VERSION 5.7 ;
  NOWIREEXTENSIONATPIN ON ;
  DIVIDERCHAR "/" ;
  BUSBITCHARS "[]" ;
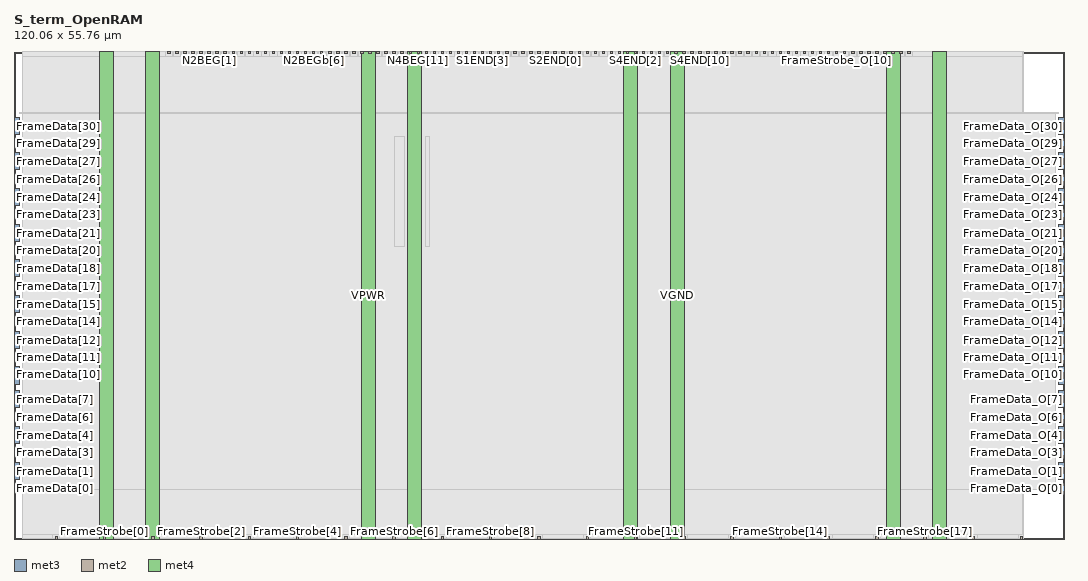
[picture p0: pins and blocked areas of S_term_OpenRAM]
MACRO S_term_OpenRAM
  CLASS BLOCK ;
  FOREIGN S_term_OpenRAM ;
  ORIGIN 0.000 0.000 ;
  SIZE 120.060 BY 55.760 ;
  PIN FrameData[0]
    DIRECTION INPUT ;
    USE SIGNAL ;
    ANTENNAGATEAREA 0.196500 ;
    PORT
      LAYER met3 ;
        RECT 0.000 5.480 0.600 6.080 ;
    END
  END FrameData[0]
  PIN FrameData[10]
    DIRECTION INPUT ;
    USE SIGNAL ;
    ANTENNAGATEAREA 0.631200 ;
    ANTENNADIFFAREA 0.434700 ;
    PORT
      LAYER met3 ;
        RECT 0.000 19.080 0.600 19.680 ;
    END
  END FrameData[10]
  PIN FrameData[11]
    DIRECTION INPUT ;
    USE SIGNAL ;
    ANTENNAGATEAREA 0.631200 ;
    ANTENNADIFFAREA 0.434700 ;
    PORT
      LAYER met3 ;
        RECT 0.000 20.440 0.600 21.040 ;
    END
  END FrameData[11]
  PIN FrameData[12]
    DIRECTION INPUT ;
    USE SIGNAL ;
    ANTENNAGATEAREA 0.631200 ;
    ANTENNADIFFAREA 0.434700 ;
    PORT
      LAYER met3 ;
        RECT 0.000 21.800 0.600 22.400 ;
    END
  END FrameData[12]
  PIN FrameData[13]
    DIRECTION INPUT ;
    USE SIGNAL ;
    ANTENNAGATEAREA 0.196500 ;
    PORT
      LAYER met3 ;
        RECT 0.000 23.160 0.600 23.760 ;
    END
  END FrameData[13]
  PIN FrameData[14]
    DIRECTION INPUT ;
    USE SIGNAL ;
    ANTENNAGATEAREA 0.196500 ;
    PORT
      LAYER met3 ;
        RECT 0.000 24.520 0.600 25.120 ;
    END
  END FrameData[14]
  PIN FrameData[15]
    DIRECTION INPUT ;
    USE SIGNAL ;
    ANTENNAGATEAREA 0.196500 ;
    PORT
      LAYER met3 ;
        RECT 0.000 25.880 0.600 26.480 ;
    END
  END FrameData[15]
  PIN FrameData[16]
    DIRECTION INPUT ;
    USE SIGNAL ;
    ANTENNAGATEAREA 0.196500 ;
    PORT
      LAYER met3 ;
        RECT 0.000 27.240 0.600 27.840 ;
    END
  END FrameData[16]
  PIN FrameData[17]
    DIRECTION INPUT ;
    USE SIGNAL ;
    ANTENNAGATEAREA 0.196500 ;
    PORT
      LAYER met3 ;
        RECT 0.000 28.600 0.600 29.200 ;
    END
  END FrameData[17]
  PIN FrameData[18]
    DIRECTION INPUT ;
    USE SIGNAL ;
    ANTENNAGATEAREA 0.196500 ;
    PORT
      LAYER met3 ;
        RECT 0.000 29.960 0.600 30.560 ;
    END
  END FrameData[18]
  PIN FrameData[19]
    DIRECTION INPUT ;
    USE SIGNAL ;
    ANTENNAGATEAREA 0.631200 ;
    ANTENNADIFFAREA 0.434700 ;
    PORT
      LAYER met3 ;
        RECT 0.000 31.320 0.600 31.920 ;
    END
  END FrameData[19]
  PIN FrameData[1]
    DIRECTION INPUT ;
    USE SIGNAL ;
    ANTENNAGATEAREA 0.196500 ;
    PORT
      LAYER met3 ;
        RECT 0.000 6.840 0.600 7.440 ;
    END
  END FrameData[1]
  PIN FrameData[20]
    DIRECTION INPUT ;
    USE SIGNAL ;
    ANTENNAGATEAREA 0.196500 ;
    PORT
      LAYER met3 ;
        RECT 0.000 32.680 0.600 33.280 ;
    END
  END FrameData[20]
  PIN FrameData[21]
    DIRECTION INPUT ;
    USE SIGNAL ;
    ANTENNAGATEAREA 0.196500 ;
    PORT
      LAYER met3 ;
        RECT 0.000 34.040 0.600 34.640 ;
    END
  END FrameData[21]
  PIN FrameData[22]
    DIRECTION INPUT ;
    USE SIGNAL ;
    ANTENNAGATEAREA 0.631200 ;
    ANTENNADIFFAREA 0.434700 ;
    PORT
      LAYER met3 ;
        RECT 0.000 35.400 0.600 36.000 ;
    END
  END FrameData[22]
  PIN FrameData[23]
    DIRECTION INPUT ;
    USE SIGNAL ;
    ANTENNAGATEAREA 0.196500 ;
    PORT
      LAYER met3 ;
        RECT 0.000 36.760 0.600 37.360 ;
    END
  END FrameData[23]
  PIN FrameData[24]
    DIRECTION INPUT ;
    USE SIGNAL ;
    ANTENNAGATEAREA 0.631200 ;
    ANTENNADIFFAREA 0.434700 ;
    PORT
      LAYER met3 ;
        RECT 0.000 38.120 0.600 38.720 ;
    END
  END FrameData[24]
  PIN FrameData[25]
    DIRECTION INPUT ;
    USE SIGNAL ;
    ANTENNAGATEAREA 0.631200 ;
    ANTENNADIFFAREA 0.434700 ;
    PORT
      LAYER met3 ;
        RECT 0.000 39.480 0.600 40.080 ;
    END
  END FrameData[25]
  PIN FrameData[26]
    DIRECTION INPUT ;
    USE SIGNAL ;
    ANTENNAGATEAREA 0.631200 ;
    ANTENNADIFFAREA 0.434700 ;
    PORT
      LAYER met3 ;
        RECT 0.000 40.840 0.600 41.440 ;
    END
  END FrameData[26]
  PIN FrameData[27]
    DIRECTION INPUT ;
    USE SIGNAL ;
    ANTENNAGATEAREA 0.631200 ;
    ANTENNADIFFAREA 0.434700 ;
    PORT
      LAYER met3 ;
        RECT 0.000 42.200 0.600 42.800 ;
    END
  END FrameData[27]
  PIN FrameData[28]
    DIRECTION INPUT ;
    USE SIGNAL ;
    ANTENNAGATEAREA 0.631200 ;
    ANTENNADIFFAREA 0.434700 ;
    PORT
      LAYER met3 ;
        RECT 0.000 43.560 0.600 44.160 ;
    END
  END FrameData[28]
  PIN FrameData[29]
    DIRECTION INPUT ;
    USE SIGNAL ;
    ANTENNAGATEAREA 0.631200 ;
    ANTENNADIFFAREA 0.434700 ;
    PORT
      LAYER met3 ;
        RECT 0.000 44.920 0.600 45.520 ;
    END
  END FrameData[29]
  PIN FrameData[2]
    DIRECTION INPUT ;
    USE SIGNAL ;
    ANTENNAGATEAREA 0.196500 ;
    PORT
      LAYER met3 ;
        RECT 0.000 8.200 0.600 8.800 ;
    END
  END FrameData[2]
  PIN FrameData[30]
    DIRECTION INPUT ;
    USE SIGNAL ;
    ANTENNAGATEAREA 0.631200 ;
    ANTENNADIFFAREA 0.434700 ;
    PORT
      LAYER met3 ;
        RECT 0.000 46.280 0.600 46.880 ;
    END
  END FrameData[30]
  PIN FrameData[31]
    DIRECTION INPUT ;
    USE SIGNAL ;
    ANTENNAGATEAREA 0.631200 ;
    ANTENNADIFFAREA 0.434700 ;
    PORT
      LAYER met3 ;
        RECT 0.000 47.640 0.600 48.240 ;
    END
  END FrameData[31]
  PIN FrameData[3]
    DIRECTION INPUT ;
    USE SIGNAL ;
    ANTENNAGATEAREA 0.631200 ;
    ANTENNADIFFAREA 0.434700 ;
    PORT
      LAYER met3 ;
        RECT 0.000 9.560 0.600 10.160 ;
    END
  END FrameData[3]
  PIN FrameData[4]
    DIRECTION INPUT ;
    USE SIGNAL ;
    ANTENNAGATEAREA 0.196500 ;
    PORT
      LAYER met3 ;
        RECT 0.000 10.920 0.600 11.520 ;
    END
  END FrameData[4]
  PIN FrameData[5]
    DIRECTION INPUT ;
    USE SIGNAL ;
    ANTENNAGATEAREA 0.631200 ;
    ANTENNADIFFAREA 0.434700 ;
    PORT
      LAYER met3 ;
        RECT 0.000 12.280 0.600 12.880 ;
    END
  END FrameData[5]
  PIN FrameData[6]
    DIRECTION INPUT ;
    USE SIGNAL ;
    ANTENNAGATEAREA 0.631200 ;
    ANTENNADIFFAREA 0.434700 ;
    PORT
      LAYER met3 ;
        RECT 0.000 13.640 0.600 14.240 ;
    END
  END FrameData[6]
  PIN FrameData[7]
    DIRECTION INPUT ;
    USE SIGNAL ;
    ANTENNAGATEAREA 0.631200 ;
    ANTENNADIFFAREA 0.434700 ;
    PORT
      LAYER met3 ;
        RECT 0.000 15.000 0.600 15.600 ;
    END
  END FrameData[7]
  PIN FrameData[8]
    DIRECTION INPUT ;
    USE SIGNAL ;
    ANTENNAGATEAREA 0.631200 ;
    ANTENNADIFFAREA 0.434700 ;
    PORT
      LAYER met3 ;
        RECT 0.000 16.360 0.600 16.960 ;
    END
  END FrameData[8]
  PIN FrameData[9]
    DIRECTION INPUT ;
    USE SIGNAL ;
    ANTENNAGATEAREA 0.196500 ;
    PORT
      LAYER met3 ;
        RECT 0.000 17.720 0.600 18.320 ;
    END
  END FrameData[9]
  PIN FrameData_O[0]
    DIRECTION OUTPUT ;
    USE SIGNAL ;
    ANTENNADIFFAREA 0.445500 ;
    PORT
      LAYER met3 ;
        RECT 119.460 5.480 120.060 6.080 ;
    END
  END FrameData_O[0]
  PIN FrameData_O[10]
    DIRECTION OUTPUT ;
    USE SIGNAL ;
    ANTENNADIFFAREA 0.445500 ;
    PORT
      LAYER met3 ;
        RECT 119.460 19.080 120.060 19.680 ;
    END
  END FrameData_O[10]
  PIN FrameData_O[11]
    DIRECTION OUTPUT ;
    USE SIGNAL ;
    ANTENNADIFFAREA 0.445500 ;
    PORT
      LAYER met3 ;
        RECT 119.460 20.440 120.060 21.040 ;
    END
  END FrameData_O[11]
  PIN FrameData_O[12]
    DIRECTION OUTPUT ;
    USE SIGNAL ;
    ANTENNADIFFAREA 0.445500 ;
    PORT
      LAYER met3 ;
        RECT 119.460 21.800 120.060 22.400 ;
    END
  END FrameData_O[12]
  PIN FrameData_O[13]
    DIRECTION OUTPUT ;
    USE SIGNAL ;
    ANTENNADIFFAREA 0.445500 ;
    PORT
      LAYER met3 ;
        RECT 119.460 23.160 120.060 23.760 ;
    END
  END FrameData_O[13]
  PIN FrameData_O[14]
    DIRECTION OUTPUT ;
    USE SIGNAL ;
    ANTENNADIFFAREA 0.445500 ;
    PORT
      LAYER met3 ;
        RECT 119.460 24.520 120.060 25.120 ;
    END
  END FrameData_O[14]
  PIN FrameData_O[15]
    DIRECTION OUTPUT ;
    USE SIGNAL ;
    ANTENNADIFFAREA 0.445500 ;
    PORT
      LAYER met3 ;
        RECT 119.460 25.880 120.060 26.480 ;
    END
  END FrameData_O[15]
  PIN FrameData_O[16]
    DIRECTION OUTPUT ;
    USE SIGNAL ;
    ANTENNADIFFAREA 0.445500 ;
    PORT
      LAYER met3 ;
        RECT 119.460 27.240 120.060 27.840 ;
    END
  END FrameData_O[16]
  PIN FrameData_O[17]
    DIRECTION OUTPUT ;
    USE SIGNAL ;
    ANTENNADIFFAREA 0.445500 ;
    PORT
      LAYER met3 ;
        RECT 119.460 28.600 120.060 29.200 ;
    END
  END FrameData_O[17]
  PIN FrameData_O[18]
    DIRECTION OUTPUT ;
    USE SIGNAL ;
    ANTENNADIFFAREA 0.445500 ;
    PORT
      LAYER met3 ;
        RECT 119.460 29.960 120.060 30.560 ;
    END
  END FrameData_O[18]
  PIN FrameData_O[19]
    DIRECTION OUTPUT ;
    USE SIGNAL ;
    ANTENNADIFFAREA 0.445500 ;
    PORT
      LAYER met3 ;
        RECT 119.460 31.320 120.060 31.920 ;
    END
  END FrameData_O[19]
  PIN FrameData_O[1]
    DIRECTION OUTPUT ;
    USE SIGNAL ;
    ANTENNADIFFAREA 0.445500 ;
    PORT
      LAYER met3 ;
        RECT 119.460 6.840 120.060 7.440 ;
    END
  END FrameData_O[1]
  PIN FrameData_O[20]
    DIRECTION OUTPUT ;
    USE SIGNAL ;
    ANTENNADIFFAREA 0.445500 ;
    PORT
      LAYER met3 ;
        RECT 119.460 32.680 120.060 33.280 ;
    END
  END FrameData_O[20]
  PIN FrameData_O[21]
    DIRECTION OUTPUT ;
    USE SIGNAL ;
    ANTENNADIFFAREA 0.445500 ;
    PORT
      LAYER met3 ;
        RECT 119.460 34.040 120.060 34.640 ;
    END
  END FrameData_O[21]
  PIN FrameData_O[22]
    DIRECTION OUTPUT ;
    USE SIGNAL ;
    ANTENNADIFFAREA 0.445500 ;
    PORT
      LAYER met3 ;
        RECT 119.460 35.400 120.060 36.000 ;
    END
  END FrameData_O[22]
  PIN FrameData_O[23]
    DIRECTION OUTPUT ;
    USE SIGNAL ;
    ANTENNADIFFAREA 0.445500 ;
    PORT
      LAYER met3 ;
        RECT 119.460 36.760 120.060 37.360 ;
    END
  END FrameData_O[23]
  PIN FrameData_O[24]
    DIRECTION OUTPUT ;
    USE SIGNAL ;
    ANTENNADIFFAREA 0.445500 ;
    PORT
      LAYER met3 ;
        RECT 119.460 38.120 120.060 38.720 ;
    END
  END FrameData_O[24]
  PIN FrameData_O[25]
    DIRECTION OUTPUT ;
    USE SIGNAL ;
    ANTENNADIFFAREA 0.445500 ;
    PORT
      LAYER met3 ;
        RECT 119.460 39.480 120.060 40.080 ;
    END
  END FrameData_O[25]
  PIN FrameData_O[26]
    DIRECTION OUTPUT ;
    USE SIGNAL ;
    ANTENNADIFFAREA 0.445500 ;
    PORT
      LAYER met3 ;
        RECT 119.460 40.840 120.060 41.440 ;
    END
  END FrameData_O[26]
  PIN FrameData_O[27]
    DIRECTION OUTPUT ;
    USE SIGNAL ;
    ANTENNADIFFAREA 0.445500 ;
    PORT
      LAYER met3 ;
        RECT 119.460 42.200 120.060 42.800 ;
    END
  END FrameData_O[27]
  PIN FrameData_O[28]
    DIRECTION OUTPUT ;
    USE SIGNAL ;
    ANTENNADIFFAREA 0.445500 ;
    PORT
      LAYER met3 ;
        RECT 119.460 43.560 120.060 44.160 ;
    END
  END FrameData_O[28]
  PIN FrameData_O[29]
    DIRECTION OUTPUT ;
    USE SIGNAL ;
    ANTENNADIFFAREA 0.445500 ;
    PORT
      LAYER met3 ;
        RECT 119.460 44.920 120.060 45.520 ;
    END
  END FrameData_O[29]
  PIN FrameData_O[2]
    DIRECTION OUTPUT ;
    USE SIGNAL ;
    ANTENNADIFFAREA 0.445500 ;
    PORT
      LAYER met3 ;
        RECT 119.460 8.200 120.060 8.800 ;
    END
  END FrameData_O[2]
  PIN FrameData_O[30]
    DIRECTION OUTPUT ;
    USE SIGNAL ;
    ANTENNADIFFAREA 0.445500 ;
    PORT
      LAYER met3 ;
        RECT 119.460 46.280 120.060 46.880 ;
    END
  END FrameData_O[30]
  PIN FrameData_O[31]
    DIRECTION OUTPUT ;
    USE SIGNAL ;
    ANTENNADIFFAREA 0.445500 ;
    PORT
      LAYER met3 ;
        RECT 119.460 47.640 120.060 48.240 ;
    END
  END FrameData_O[31]
  PIN FrameData_O[3]
    DIRECTION OUTPUT ;
    USE SIGNAL ;
    ANTENNADIFFAREA 0.445500 ;
    PORT
      LAYER met3 ;
        RECT 119.460 9.560 120.060 10.160 ;
    END
  END FrameData_O[3]
  PIN FrameData_O[4]
    DIRECTION OUTPUT ;
    USE SIGNAL ;
    ANTENNADIFFAREA 0.445500 ;
    PORT
      LAYER met3 ;
        RECT 119.460 10.920 120.060 11.520 ;
    END
  END FrameData_O[4]
  PIN FrameData_O[5]
    DIRECTION OUTPUT ;
    USE SIGNAL ;
    ANTENNADIFFAREA 0.445500 ;
    PORT
      LAYER met3 ;
        RECT 119.460 12.280 120.060 12.880 ;
    END
  END FrameData_O[5]
  PIN FrameData_O[6]
    DIRECTION OUTPUT ;
    USE SIGNAL ;
    ANTENNADIFFAREA 0.445500 ;
    PORT
      LAYER met3 ;
        RECT 119.460 13.640 120.060 14.240 ;
    END
  END FrameData_O[6]
  PIN FrameData_O[7]
    DIRECTION OUTPUT ;
    USE SIGNAL ;
    ANTENNADIFFAREA 0.445500 ;
    PORT
      LAYER met3 ;
        RECT 119.460 15.000 120.060 15.600 ;
    END
  END FrameData_O[7]
  PIN FrameData_O[8]
    DIRECTION OUTPUT ;
    USE SIGNAL ;
    ANTENNADIFFAREA 0.445500 ;
    PORT
      LAYER met3 ;
        RECT 119.460 16.360 120.060 16.960 ;
    END
  END FrameData_O[8]
  PIN FrameData_O[9]
    DIRECTION OUTPUT ;
    USE SIGNAL ;
    ANTENNADIFFAREA 0.445500 ;
    PORT
      LAYER met3 ;
        RECT 119.460 17.720 120.060 18.320 ;
    END
  END FrameData_O[9]
  PIN FrameStrobe[0]
    DIRECTION INPUT ;
    USE SIGNAL ;
    ANTENNAGATEAREA 0.196500 ;
    PORT
      LAYER met2 ;
        RECT 10.210 0.000 10.490 0.280 ;
    END
  END FrameStrobe[0]
  PIN FrameStrobe[10]
    DIRECTION INPUT ;
    USE SIGNAL ;
    ANTENNAGATEAREA 0.196500 ;
    PORT
      LAYER met2 ;
        RECT 65.410 0.000 65.690 0.280 ;
    END
  END FrameStrobe[10]
  PIN FrameStrobe[11]
    DIRECTION INPUT ;
    USE SIGNAL ;
    ANTENNAGATEAREA 0.196500 ;
    PORT
      LAYER met2 ;
        RECT 70.930 0.000 71.210 0.280 ;
    END
  END FrameStrobe[11]
  PIN FrameStrobe[12]
    DIRECTION INPUT ;
    USE SIGNAL ;
    ANTENNAGATEAREA 0.196500 ;
    PORT
      LAYER met2 ;
        RECT 76.450 0.000 76.730 0.280 ;
    END
  END FrameStrobe[12]
  PIN FrameStrobe[13]
    DIRECTION INPUT ;
    USE SIGNAL ;
    ANTENNAGATEAREA 0.196500 ;
    PORT
      LAYER met2 ;
        RECT 81.970 0.000 82.250 0.280 ;
    END
  END FrameStrobe[13]
  PIN FrameStrobe[14]
    DIRECTION INPUT ;
    USE SIGNAL ;
    ANTENNAGATEAREA 0.196500 ;
    PORT
      LAYER met2 ;
        RECT 87.490 0.000 87.770 0.280 ;
    END
  END FrameStrobe[14]
  PIN FrameStrobe[15]
    DIRECTION INPUT ;
    USE SIGNAL ;
    ANTENNAGATEAREA 0.196500 ;
    PORT
      LAYER met2 ;
        RECT 93.010 0.000 93.290 0.280 ;
    END
  END FrameStrobe[15]
  PIN FrameStrobe[16]
    DIRECTION INPUT ;
    USE SIGNAL ;
    ANTENNAGATEAREA 0.196500 ;
    PORT
      LAYER met2 ;
        RECT 98.530 0.000 98.810 0.280 ;
    END
  END FrameStrobe[16]
  PIN FrameStrobe[17]
    DIRECTION INPUT ;
    USE SIGNAL ;
    ANTENNAGATEAREA 0.196500 ;
    PORT
      LAYER met2 ;
        RECT 104.050 0.000 104.330 0.280 ;
    END
  END FrameStrobe[17]
  PIN FrameStrobe[18]
    DIRECTION INPUT ;
    USE SIGNAL ;
    ANTENNAGATEAREA 0.196500 ;
    PORT
      LAYER met2 ;
        RECT 109.570 0.000 109.850 0.280 ;
    END
  END FrameStrobe[18]
  PIN FrameStrobe[19]
    DIRECTION INPUT ;
    USE SIGNAL ;
    ANTENNAGATEAREA 0.196500 ;
    PORT
      LAYER met2 ;
        RECT 115.090 0.000 115.370 0.280 ;
    END
  END FrameStrobe[19]
  PIN FrameStrobe[1]
    DIRECTION INPUT ;
    USE SIGNAL ;
    ANTENNAGATEAREA 0.196500 ;
    PORT
      LAYER met2 ;
        RECT 15.730 0.000 16.010 0.280 ;
    END
  END FrameStrobe[1]
  PIN FrameStrobe[2]
    DIRECTION INPUT ;
    USE SIGNAL ;
    ANTENNAGATEAREA 0.196500 ;
    PORT
      LAYER met2 ;
        RECT 21.250 0.000 21.530 0.280 ;
    END
  END FrameStrobe[2]
  PIN FrameStrobe[3]
    DIRECTION INPUT ;
    USE SIGNAL ;
    ANTENNAGATEAREA 0.196500 ;
    PORT
      LAYER met2 ;
        RECT 26.770 0.000 27.050 0.280 ;
    END
  END FrameStrobe[3]
  PIN FrameStrobe[4]
    DIRECTION INPUT ;
    USE SIGNAL ;
    ANTENNAGATEAREA 0.196500 ;
    PORT
      LAYER met2 ;
        RECT 32.290 0.000 32.570 0.280 ;
    END
  END FrameStrobe[4]
  PIN FrameStrobe[5]
    DIRECTION INPUT ;
    USE SIGNAL ;
    ANTENNAGATEAREA 0.196500 ;
    PORT
      LAYER met2 ;
        RECT 37.810 0.000 38.090 0.280 ;
    END
  END FrameStrobe[5]
  PIN FrameStrobe[6]
    DIRECTION INPUT ;
    USE SIGNAL ;
    ANTENNAGATEAREA 0.196500 ;
    PORT
      LAYER met2 ;
        RECT 43.330 0.000 43.610 0.280 ;
    END
  END FrameStrobe[6]
  PIN FrameStrobe[7]
    DIRECTION INPUT ;
    USE SIGNAL ;
    ANTENNAGATEAREA 0.196500 ;
    PORT
      LAYER met2 ;
        RECT 48.850 0.000 49.130 0.280 ;
    END
  END FrameStrobe[7]
  PIN FrameStrobe[8]
    DIRECTION INPUT ;
    USE SIGNAL ;
    ANTENNAGATEAREA 0.196500 ;
    PORT
      LAYER met2 ;
        RECT 54.370 0.000 54.650 0.280 ;
    END
  END FrameStrobe[8]
  PIN FrameStrobe[9]
    DIRECTION INPUT ;
    USE SIGNAL ;
    ANTENNAGATEAREA 0.196500 ;
    PORT
      LAYER met2 ;
        RECT 59.890 0.000 60.170 0.280 ;
    END
  END FrameStrobe[9]
  PIN FrameStrobe_O[0]
    DIRECTION OUTPUT ;
    USE SIGNAL ;
    ANTENNADIFFAREA 0.445500 ;
    PORT
      LAYER met2 ;
        RECT 84.730 55.480 85.010 55.760 ;
    END
  END FrameStrobe_O[0]
  PIN FrameStrobe_O[10]
    DIRECTION OUTPUT ;
    USE SIGNAL ;
    ANTENNADIFFAREA 0.445500 ;
    PORT
      LAYER met2 ;
        RECT 93.930 55.480 94.210 55.760 ;
    END
  END FrameStrobe_O[10]
  PIN FrameStrobe_O[11]
    DIRECTION OUTPUT ;
    USE SIGNAL ;
    ANTENNADIFFAREA 0.445500 ;
    PORT
      LAYER met2 ;
        RECT 94.850 55.480 95.130 55.760 ;
    END
  END FrameStrobe_O[11]
  PIN FrameStrobe_O[12]
    DIRECTION OUTPUT ;
    USE SIGNAL ;
    ANTENNADIFFAREA 0.445500 ;
    PORT
      LAYER met2 ;
        RECT 95.770 55.480 96.050 55.760 ;
    END
  END FrameStrobe_O[12]
  PIN FrameStrobe_O[13]
    DIRECTION OUTPUT ;
    USE SIGNAL ;
    ANTENNADIFFAREA 0.445500 ;
    PORT
      LAYER met2 ;
        RECT 96.690 55.480 96.970 55.760 ;
    END
  END FrameStrobe_O[13]
  PIN FrameStrobe_O[14]
    DIRECTION OUTPUT ;
    USE SIGNAL ;
    ANTENNADIFFAREA 0.445500 ;
    PORT
      LAYER met2 ;
        RECT 97.610 55.480 97.890 55.760 ;
    END
  END FrameStrobe_O[14]
  PIN FrameStrobe_O[15]
    DIRECTION OUTPUT ;
    USE SIGNAL ;
    ANTENNADIFFAREA 0.445500 ;
    PORT
      LAYER met2 ;
        RECT 98.530 55.480 98.810 55.760 ;
    END
  END FrameStrobe_O[15]
  PIN FrameStrobe_O[16]
    DIRECTION OUTPUT ;
    USE SIGNAL ;
    ANTENNADIFFAREA 0.445500 ;
    PORT
      LAYER met2 ;
        RECT 99.450 55.480 99.730 55.760 ;
    END
  END FrameStrobe_O[16]
  PIN FrameStrobe_O[17]
    DIRECTION OUTPUT ;
    USE SIGNAL ;
    ANTENNADIFFAREA 0.445500 ;
    PORT
      LAYER met2 ;
        RECT 100.370 55.480 100.650 55.760 ;
    END
  END FrameStrobe_O[17]
  PIN FrameStrobe_O[18]
    DIRECTION OUTPUT ;
    USE SIGNAL ;
    ANTENNADIFFAREA 0.445500 ;
    PORT
      LAYER met2 ;
        RECT 101.290 55.480 101.570 55.760 ;
    END
  END FrameStrobe_O[18]
  PIN FrameStrobe_O[19]
    DIRECTION OUTPUT ;
    USE SIGNAL ;
    ANTENNADIFFAREA 0.445500 ;
    PORT
      LAYER met2 ;
        RECT 102.210 55.480 102.490 55.760 ;
    END
  END FrameStrobe_O[19]
  PIN FrameStrobe_O[1]
    DIRECTION OUTPUT ;
    USE SIGNAL ;
    ANTENNADIFFAREA 0.445500 ;
    PORT
      LAYER met2 ;
        RECT 85.650 55.480 85.930 55.760 ;
    END
  END FrameStrobe_O[1]
  PIN FrameStrobe_O[2]
    DIRECTION OUTPUT ;
    USE SIGNAL ;
    ANTENNADIFFAREA 0.445500 ;
    PORT
      LAYER met2 ;
        RECT 86.570 55.480 86.850 55.760 ;
    END
  END FrameStrobe_O[2]
  PIN FrameStrobe_O[3]
    DIRECTION OUTPUT ;
    USE SIGNAL ;
    ANTENNADIFFAREA 0.445500 ;
    PORT
      LAYER met2 ;
        RECT 87.490 55.480 87.770 55.760 ;
    END
  END FrameStrobe_O[3]
  PIN FrameStrobe_O[4]
    DIRECTION OUTPUT ;
    USE SIGNAL ;
    ANTENNADIFFAREA 0.445500 ;
    PORT
      LAYER met2 ;
        RECT 88.410 55.480 88.690 55.760 ;
    END
  END FrameStrobe_O[4]
  PIN FrameStrobe_O[5]
    DIRECTION OUTPUT ;
    USE SIGNAL ;
    ANTENNADIFFAREA 0.445500 ;
    PORT
      LAYER met2 ;
        RECT 89.330 55.480 89.610 55.760 ;
    END
  END FrameStrobe_O[5]
  PIN FrameStrobe_O[6]
    DIRECTION OUTPUT ;
    USE SIGNAL ;
    ANTENNADIFFAREA 0.445500 ;
    PORT
      LAYER met2 ;
        RECT 90.250 55.480 90.530 55.760 ;
    END
  END FrameStrobe_O[6]
  PIN FrameStrobe_O[7]
    DIRECTION OUTPUT ;
    USE SIGNAL ;
    ANTENNADIFFAREA 0.445500 ;
    PORT
      LAYER met2 ;
        RECT 91.170 55.480 91.450 55.760 ;
    END
  END FrameStrobe_O[7]
  PIN FrameStrobe_O[8]
    DIRECTION OUTPUT ;
    USE SIGNAL ;
    ANTENNADIFFAREA 0.445500 ;
    PORT
      LAYER met2 ;
        RECT 92.090 55.480 92.370 55.760 ;
    END
  END FrameStrobe_O[8]
  PIN FrameStrobe_O[9]
    DIRECTION OUTPUT ;
    USE SIGNAL ;
    ANTENNADIFFAREA 0.445500 ;
    PORT
      LAYER met2 ;
        RECT 93.010 55.480 93.290 55.760 ;
    END
  END FrameStrobe_O[9]
  PIN N1BEG[0]
    DIRECTION OUTPUT ;
    USE SIGNAL ;
    ANTENNADIFFAREA 0.445500 ;
    PORT
      LAYER met2 ;
        RECT 17.570 55.480 17.850 55.760 ;
    END
  END N1BEG[0]
  PIN N1BEG[1]
    DIRECTION OUTPUT ;
    USE SIGNAL ;
    ANTENNADIFFAREA 0.445500 ;
    PORT
      LAYER met2 ;
        RECT 18.490 55.480 18.770 55.760 ;
    END
  END N1BEG[1]
  PIN N1BEG[2]
    DIRECTION OUTPUT ;
    USE SIGNAL ;
    ANTENNADIFFAREA 0.445500 ;
    PORT
      LAYER met2 ;
        RECT 19.410 55.480 19.690 55.760 ;
    END
  END N1BEG[2]
  PIN N1BEG[3]
    DIRECTION OUTPUT ;
    USE SIGNAL ;
    ANTENNADIFFAREA 0.445500 ;
    PORT
      LAYER met2 ;
        RECT 20.330 55.480 20.610 55.760 ;
    END
  END N1BEG[3]
  PIN N2BEG[0]
    DIRECTION OUTPUT ;
    USE SIGNAL ;
    ANTENNADIFFAREA 0.445500 ;
    PORT
      LAYER met2 ;
        RECT 21.250 55.480 21.530 55.760 ;
    END
  END N2BEG[0]
  PIN N2BEG[1]
    DIRECTION OUTPUT ;
    USE SIGNAL ;
    ANTENNADIFFAREA 0.445500 ;
    PORT
      LAYER met2 ;
        RECT 22.170 55.480 22.450 55.760 ;
    END
  END N2BEG[1]
  PIN N2BEG[2]
    DIRECTION OUTPUT ;
    USE SIGNAL ;
    ANTENNADIFFAREA 0.445500 ;
    PORT
      LAYER met2 ;
        RECT 23.090 55.480 23.370 55.760 ;
    END
  END N2BEG[2]
  PIN N2BEG[3]
    DIRECTION OUTPUT ;
    USE SIGNAL ;
    ANTENNADIFFAREA 0.445500 ;
    PORT
      LAYER met2 ;
        RECT 24.010 55.480 24.290 55.760 ;
    END
  END N2BEG[3]
  PIN N2BEG[4]
    DIRECTION OUTPUT ;
    USE SIGNAL ;
    ANTENNADIFFAREA 0.445500 ;
    PORT
      LAYER met2 ;
        RECT 24.930 55.480 25.210 55.760 ;
    END
  END N2BEG[4]
  PIN N2BEG[5]
    DIRECTION OUTPUT ;
    USE SIGNAL ;
    ANTENNADIFFAREA 0.445500 ;
    PORT
      LAYER met2 ;
        RECT 25.850 55.480 26.130 55.760 ;
    END
  END N2BEG[5]
  PIN N2BEG[6]
    DIRECTION OUTPUT ;
    USE SIGNAL ;
    ANTENNADIFFAREA 0.445500 ;
    PORT
      LAYER met2 ;
        RECT 26.770 55.480 27.050 55.760 ;
    END
  END N2BEG[6]
  PIN N2BEG[7]
    DIRECTION OUTPUT ;
    USE SIGNAL ;
    ANTENNADIFFAREA 0.445500 ;
    PORT
      LAYER met2 ;
        RECT 27.690 55.480 27.970 55.760 ;
    END
  END N2BEG[7]
  PIN N2BEGb[0]
    DIRECTION OUTPUT ;
    USE SIGNAL ;
    ANTENNADIFFAREA 0.445500 ;
    PORT
      LAYER met2 ;
        RECT 28.610 55.480 28.890 55.760 ;
    END
  END N2BEGb[0]
  PIN N2BEGb[1]
    DIRECTION OUTPUT ;
    USE SIGNAL ;
    ANTENNADIFFAREA 0.445500 ;
    PORT
      LAYER met2 ;
        RECT 29.530 55.480 29.810 55.760 ;
    END
  END N2BEGb[1]
  PIN N2BEGb[2]
    DIRECTION OUTPUT ;
    USE SIGNAL ;
    ANTENNADIFFAREA 0.445500 ;
    PORT
      LAYER met2 ;
        RECT 30.450 55.480 30.730 55.760 ;
    END
  END N2BEGb[2]
  PIN N2BEGb[3]
    DIRECTION OUTPUT ;
    USE SIGNAL ;
    ANTENNADIFFAREA 0.445500 ;
    PORT
      LAYER met2 ;
        RECT 31.370 55.480 31.650 55.760 ;
    END
  END N2BEGb[3]
  PIN N2BEGb[4]
    DIRECTION OUTPUT ;
    USE SIGNAL ;
    ANTENNADIFFAREA 0.445500 ;
    PORT
      LAYER met2 ;
        RECT 32.290 55.480 32.570 55.760 ;
    END
  END N2BEGb[4]
  PIN N2BEGb[5]
    DIRECTION OUTPUT ;
    USE SIGNAL ;
    ANTENNADIFFAREA 0.445500 ;
    PORT
      LAYER met2 ;
        RECT 33.210 55.480 33.490 55.760 ;
    END
  END N2BEGb[5]
  PIN N2BEGb[6]
    DIRECTION OUTPUT ;
    USE SIGNAL ;
    ANTENNADIFFAREA 0.445500 ;
    PORT
      LAYER met2 ;
        RECT 34.130 55.480 34.410 55.760 ;
    END
  END N2BEGb[6]
  PIN N2BEGb[7]
    DIRECTION OUTPUT ;
    USE SIGNAL ;
    ANTENNADIFFAREA 0.445500 ;
    PORT
      LAYER met2 ;
        RECT 35.050 55.480 35.330 55.760 ;
    END
  END N2BEGb[7]
  PIN N4BEG[0]
    DIRECTION OUTPUT ;
    USE SIGNAL ;
    ANTENNADIFFAREA 0.445500 ;
    PORT
      LAYER met2 ;
        RECT 35.970 55.480 36.250 55.760 ;
    END
  END N4BEG[0]
  PIN N4BEG[10]
    DIRECTION OUTPUT ;
    USE SIGNAL ;
    ANTENNADIFFAREA 0.445500 ;
    PORT
      LAYER met2 ;
        RECT 45.170 55.480 45.450 55.760 ;
    END
  END N4BEG[10]
  PIN N4BEG[11]
    DIRECTION OUTPUT ;
    USE SIGNAL ;
    ANTENNADIFFAREA 0.445500 ;
    PORT
      LAYER met2 ;
        RECT 46.090 55.480 46.370 55.760 ;
    END
  END N4BEG[11]
  PIN N4BEG[12]
    DIRECTION OUTPUT ;
    USE SIGNAL ;
    ANTENNADIFFAREA 0.445500 ;
    PORT
      LAYER met2 ;
        RECT 47.010 55.480 47.290 55.760 ;
    END
  END N4BEG[12]
  PIN N4BEG[13]
    DIRECTION OUTPUT ;
    USE SIGNAL ;
    ANTENNADIFFAREA 0.445500 ;
    PORT
      LAYER met2 ;
        RECT 47.930 55.480 48.210 55.760 ;
    END
  END N4BEG[13]
  PIN N4BEG[14]
    DIRECTION OUTPUT ;
    USE SIGNAL ;
    ANTENNADIFFAREA 0.445500 ;
    PORT
      LAYER met2 ;
        RECT 48.850 55.480 49.130 55.760 ;
    END
  END N4BEG[14]
  PIN N4BEG[15]
    DIRECTION OUTPUT ;
    USE SIGNAL ;
    ANTENNADIFFAREA 0.445500 ;
    PORT
      LAYER met2 ;
        RECT 49.770 55.480 50.050 55.760 ;
    END
  END N4BEG[15]
  PIN N4BEG[1]
    DIRECTION OUTPUT ;
    USE SIGNAL ;
    ANTENNADIFFAREA 0.445500 ;
    PORT
      LAYER met2 ;
        RECT 36.890 55.480 37.170 55.760 ;
    END
  END N4BEG[1]
  PIN N4BEG[2]
    DIRECTION OUTPUT ;
    USE SIGNAL ;
    ANTENNADIFFAREA 0.445500 ;
    PORT
      LAYER met2 ;
        RECT 37.810 55.480 38.090 55.760 ;
    END
  END N4BEG[2]
  PIN N4BEG[3]
    DIRECTION OUTPUT ;
    USE SIGNAL ;
    ANTENNADIFFAREA 0.445500 ;
    PORT
      LAYER met2 ;
        RECT 38.730 55.480 39.010 55.760 ;
    END
  END N4BEG[3]
  PIN N4BEG[4]
    DIRECTION OUTPUT ;
    USE SIGNAL ;
    ANTENNADIFFAREA 0.445500 ;
    PORT
      LAYER met2 ;
        RECT 39.650 55.480 39.930 55.760 ;
    END
  END N4BEG[4]
  PIN N4BEG[5]
    DIRECTION OUTPUT ;
    USE SIGNAL ;
    ANTENNADIFFAREA 0.445500 ;
    PORT
      LAYER met2 ;
        RECT 40.570 55.480 40.850 55.760 ;
    END
  END N4BEG[5]
  PIN N4BEG[6]
    DIRECTION OUTPUT ;
    USE SIGNAL ;
    ANTENNADIFFAREA 0.445500 ;
    PORT
      LAYER met2 ;
        RECT 41.490 55.480 41.770 55.760 ;
    END
  END N4BEG[6]
  PIN N4BEG[7]
    DIRECTION OUTPUT ;
    USE SIGNAL ;
    ANTENNADIFFAREA 0.445500 ;
    PORT
      LAYER met2 ;
        RECT 42.410 55.480 42.690 55.760 ;
    END
  END N4BEG[7]
  PIN N4BEG[8]
    DIRECTION OUTPUT ;
    USE SIGNAL ;
    ANTENNADIFFAREA 0.445500 ;
    PORT
      LAYER met2 ;
        RECT 43.330 55.480 43.610 55.760 ;
    END
  END N4BEG[8]
  PIN N4BEG[9]
    DIRECTION OUTPUT ;
    USE SIGNAL ;
    ANTENNADIFFAREA 0.445500 ;
    PORT
      LAYER met2 ;
        RECT 44.250 55.480 44.530 55.760 ;
    END
  END N4BEG[9]
  PIN S1END[0]
    DIRECTION INPUT ;
    USE SIGNAL ;
    ANTENNAGATEAREA 0.196500 ;
    PORT
      LAYER met2 ;
        RECT 50.690 55.480 50.970 55.760 ;
    END
  END S1END[0]
  PIN S1END[1]
    DIRECTION INPUT ;
    USE SIGNAL ;
    ANTENNAGATEAREA 0.196500 ;
    PORT
      LAYER met2 ;
        RECT 51.610 55.480 51.890 55.760 ;
    END
  END S1END[1]
  PIN S1END[2]
    DIRECTION INPUT ;
    USE SIGNAL ;
    ANTENNAGATEAREA 0.196500 ;
    PORT
      LAYER met2 ;
        RECT 52.530 55.480 52.810 55.760 ;
    END
  END S1END[2]
  PIN S1END[3]
    DIRECTION INPUT ;
    USE SIGNAL ;
    ANTENNAGATEAREA 0.196500 ;
    PORT
      LAYER met2 ;
        RECT 53.450 55.480 53.730 55.760 ;
    END
  END S1END[3]
  PIN S2END[0]
    DIRECTION INPUT ;
    USE SIGNAL ;
    ANTENNAGATEAREA 0.196500 ;
    PORT
      LAYER met2 ;
        RECT 61.730 55.480 62.010 55.760 ;
    END
  END S2END[0]
  PIN S2END[1]
    DIRECTION INPUT ;
    USE SIGNAL ;
    ANTENNAGATEAREA 0.196500 ;
    PORT
      LAYER met2 ;
        RECT 62.650 55.480 62.930 55.760 ;
    END
  END S2END[1]
  PIN S2END[2]
    DIRECTION INPUT ;
    USE SIGNAL ;
    ANTENNAGATEAREA 0.196500 ;
    PORT
      LAYER met2 ;
        RECT 63.570 55.480 63.850 55.760 ;
    END
  END S2END[2]
  PIN S2END[3]
    DIRECTION INPUT ;
    USE SIGNAL ;
    ANTENNAGATEAREA 0.196500 ;
    PORT
      LAYER met2 ;
        RECT 64.490 55.480 64.770 55.760 ;
    END
  END S2END[3]
  PIN S2END[4]
    DIRECTION INPUT ;
    USE SIGNAL ;
    ANTENNAGATEAREA 0.196500 ;
    PORT
      LAYER met2 ;
        RECT 65.410 55.480 65.690 55.760 ;
    END
  END S2END[4]
  PIN S2END[5]
    DIRECTION INPUT ;
    USE SIGNAL ;
    ANTENNAGATEAREA 0.196500 ;
    PORT
      LAYER met2 ;
        RECT 66.330 55.480 66.610 55.760 ;
    END
  END S2END[5]
  PIN S2END[6]
    DIRECTION INPUT ;
    USE SIGNAL ;
    ANTENNAGATEAREA 0.196500 ;
    PORT
      LAYER met2 ;
        RECT 67.250 55.480 67.530 55.760 ;
    END
  END S2END[6]
  PIN S2END[7]
    DIRECTION INPUT ;
    USE SIGNAL ;
    ANTENNAGATEAREA 0.196500 ;
    PORT
      LAYER met2 ;
        RECT 68.170 55.480 68.450 55.760 ;
    END
  END S2END[7]
  PIN S2MID[0]
    DIRECTION INPUT ;
    USE SIGNAL ;
    ANTENNAGATEAREA 0.196500 ;
    PORT
      LAYER met2 ;
        RECT 54.370 55.480 54.650 55.760 ;
    END
  END S2MID[0]
  PIN S2MID[1]
    DIRECTION INPUT ;
    USE SIGNAL ;
    ANTENNAGATEAREA 0.196500 ;
    PORT
      LAYER met2 ;
        RECT 55.290 55.480 55.570 55.760 ;
    END
  END S2MID[1]
  PIN S2MID[2]
    DIRECTION INPUT ;
    USE SIGNAL ;
    ANTENNAGATEAREA 0.196500 ;
    PORT
      LAYER met2 ;
        RECT 56.210 55.480 56.490 55.760 ;
    END
  END S2MID[2]
  PIN S2MID[3]
    DIRECTION INPUT ;
    USE SIGNAL ;
    ANTENNAGATEAREA 0.196500 ;
    PORT
      LAYER met2 ;
        RECT 57.130 55.480 57.410 55.760 ;
    END
  END S2MID[3]
  PIN S2MID[4]
    DIRECTION INPUT ;
    USE SIGNAL ;
    ANTENNAGATEAREA 0.196500 ;
    PORT
      LAYER met2 ;
        RECT 58.050 55.480 58.330 55.760 ;
    END
  END S2MID[4]
  PIN S2MID[5]
    DIRECTION INPUT ;
    USE SIGNAL ;
    ANTENNAGATEAREA 0.196500 ;
    PORT
      LAYER met2 ;
        RECT 58.970 55.480 59.250 55.760 ;
    END
  END S2MID[5]
  PIN S2MID[6]
    DIRECTION INPUT ;
    USE SIGNAL ;
    ANTENNAGATEAREA 0.196500 ;
    PORT
      LAYER met2 ;
        RECT 59.890 55.480 60.170 55.760 ;
    END
  END S2MID[6]
  PIN S2MID[7]
    DIRECTION INPUT ;
    USE SIGNAL ;
    ANTENNAGATEAREA 0.196500 ;
    PORT
      LAYER met2 ;
        RECT 60.810 55.480 61.090 55.760 ;
    END
  END S2MID[7]
  PIN S4END[0]
    DIRECTION INPUT ;
    USE SIGNAL ;
    ANTENNAGATEAREA 0.196500 ;
    PORT
      LAYER met2 ;
        RECT 69.090 55.480 69.370 55.760 ;
    END
  END S4END[0]
  PIN S4END[10]
    DIRECTION INPUT ;
    USE SIGNAL ;
    ANTENNAGATEAREA 0.196500 ;
    PORT
      LAYER met2 ;
        RECT 78.290 55.480 78.570 55.760 ;
    END
  END S4END[10]
  PIN S4END[11]
    DIRECTION INPUT ;
    USE SIGNAL ;
    ANTENNAGATEAREA 0.196500 ;
    PORT
      LAYER met2 ;
        RECT 79.210 55.480 79.490 55.760 ;
    END
  END S4END[11]
  PIN S4END[12]
    DIRECTION INPUT ;
    USE SIGNAL ;
    ANTENNAGATEAREA 0.196500 ;
    PORT
      LAYER met2 ;
        RECT 80.130 55.480 80.410 55.760 ;
    END
  END S4END[12]
  PIN S4END[13]
    DIRECTION INPUT ;
    USE SIGNAL ;
    ANTENNAGATEAREA 0.196500 ;
    PORT
      LAYER met2 ;
        RECT 81.050 55.480 81.330 55.760 ;
    END
  END S4END[13]
  PIN S4END[14]
    DIRECTION INPUT ;
    USE SIGNAL ;
    ANTENNAGATEAREA 0.196500 ;
    PORT
      LAYER met2 ;
        RECT 81.970 55.480 82.250 55.760 ;
    END
  END S4END[14]
  PIN S4END[15]
    DIRECTION INPUT ;
    USE SIGNAL ;
    ANTENNAGATEAREA 0.196500 ;
    PORT
      LAYER met2 ;
        RECT 82.890 55.480 83.170 55.760 ;
    END
  END S4END[15]
  PIN S4END[1]
    DIRECTION INPUT ;
    USE SIGNAL ;
    ANTENNAGATEAREA 0.196500 ;
    PORT
      LAYER met2 ;
        RECT 70.010 55.480 70.290 55.760 ;
    END
  END S4END[1]
  PIN S4END[2]
    DIRECTION INPUT ;
    USE SIGNAL ;
    ANTENNAGATEAREA 0.196500 ;
    PORT
      LAYER met2 ;
        RECT 70.930 55.480 71.210 55.760 ;
    END
  END S4END[2]
  PIN S4END[3]
    DIRECTION INPUT ;
    USE SIGNAL ;
    ANTENNAGATEAREA 0.196500 ;
    PORT
      LAYER met2 ;
        RECT 71.850 55.480 72.130 55.760 ;
    END
  END S4END[3]
  PIN S4END[4]
    DIRECTION INPUT ;
    USE SIGNAL ;
    ANTENNAGATEAREA 0.196500 ;
    PORT
      LAYER met2 ;
        RECT 72.770 55.480 73.050 55.760 ;
    END
  END S4END[4]
  PIN S4END[5]
    DIRECTION INPUT ;
    USE SIGNAL ;
    ANTENNAGATEAREA 0.196500 ;
    PORT
      LAYER met2 ;
        RECT 73.690 55.480 73.970 55.760 ;
    END
  END S4END[5]
  PIN S4END[6]
    DIRECTION INPUT ;
    USE SIGNAL ;
    ANTENNAGATEAREA 0.196500 ;
    PORT
      LAYER met2 ;
        RECT 74.610 55.480 74.890 55.760 ;
    END
  END S4END[6]
  PIN S4END[7]
    DIRECTION INPUT ;
    USE SIGNAL ;
    ANTENNAGATEAREA 0.196500 ;
    PORT
      LAYER met2 ;
        RECT 75.530 55.480 75.810 55.760 ;
    END
  END S4END[7]
  PIN S4END[8]
    DIRECTION INPUT ;
    USE SIGNAL ;
    ANTENNAGATEAREA 0.196500 ;
    PORT
      LAYER met2 ;
        RECT 76.450 55.480 76.730 55.760 ;
    END
  END S4END[8]
  PIN S4END[9]
    DIRECTION INPUT ;
    USE SIGNAL ;
    ANTENNAGATEAREA 0.196500 ;
    PORT
      LAYER met2 ;
        RECT 77.370 55.480 77.650 55.760 ;
    END
  END S4END[9]
  PIN UserCLK
    DIRECTION INPUT ;
    USE SIGNAL ;
    ANTENNAGATEAREA 0.159000 ;
    PORT
      LAYER met2 ;
        RECT 4.690 0.000 4.970 0.280 ;
    END
  END UserCLK
  PIN UserCLKo
    DIRECTION OUTPUT ;
    USE SIGNAL ;
    ANTENNADIFFAREA 0.340600 ;
    PORT
      LAYER met2 ;
        RECT 83.810 55.480 84.090 55.760 ;
    END
  END UserCLKo
  PIN VGND
    DIRECTION INOUT ;
    USE GROUND ;
    PORT
      LAYER met4 ;
        RECT 15.020 0.000 16.620 55.760 ;
    END
    PORT
      LAYER met4 ;
        RECT 45.020 0.000 46.620 55.760 ;
    END
    PORT
      LAYER met4 ;
        RECT 75.020 0.000 76.620 55.760 ;
    END
    PORT
      LAYER met4 ;
        RECT 105.020 0.000 106.620 55.760 ;
    END
  END VGND
  PIN VPWR
    DIRECTION INOUT ;
    USE POWER ;
    PORT
      LAYER met4 ;
        RECT 9.720 0.000 11.320 55.760 ;
    END
    PORT
      LAYER met4 ;
        RECT 39.720 0.000 41.320 55.760 ;
    END
    PORT
      LAYER met4 ;
        RECT 69.720 0.000 71.320 55.760 ;
    END
    PORT
      LAYER met4 ;
        RECT 99.720 0.000 101.320 55.760 ;
    END
  END VPWR
  OBS
      LAYER nwell ;
        RECT 5.330 10.795 114.730 43.605 ;
      LAYER li1 ;
        RECT 5.520 10.795 114.540 43.605 ;
      LAYER met1 ;
        RECT 0.990 0.040 115.390 55.720 ;
      LAYER met2 ;
        RECT 1.010 55.200 17.290 55.750 ;
        RECT 18.130 55.200 18.210 55.750 ;
        RECT 19.050 55.200 19.130 55.750 ;
        RECT 19.970 55.200 20.050 55.750 ;
        RECT 20.890 55.200 20.970 55.750 ;
        RECT 21.810 55.200 21.890 55.750 ;
        RECT 22.730 55.200 22.810 55.750 ;
        RECT 23.650 55.200 23.730 55.750 ;
        RECT 24.570 55.200 24.650 55.750 ;
        RECT 25.490 55.200 25.570 55.750 ;
        RECT 26.410 55.200 26.490 55.750 ;
        RECT 27.330 55.200 27.410 55.750 ;
        RECT 28.250 55.200 28.330 55.750 ;
        RECT 29.170 55.200 29.250 55.750 ;
        RECT 30.090 55.200 30.170 55.750 ;
        RECT 31.010 55.200 31.090 55.750 ;
        RECT 31.930 55.200 32.010 55.750 ;
        RECT 32.850 55.200 32.930 55.750 ;
        RECT 33.770 55.200 33.850 55.750 ;
        RECT 34.690 55.200 34.770 55.750 ;
        RECT 35.610 55.200 35.690 55.750 ;
        RECT 36.530 55.200 36.610 55.750 ;
        RECT 37.450 55.200 37.530 55.750 ;
        RECT 38.370 55.200 38.450 55.750 ;
        RECT 39.290 55.200 39.370 55.750 ;
        RECT 40.210 55.200 40.290 55.750 ;
        RECT 41.130 55.200 41.210 55.750 ;
        RECT 42.050 55.200 42.130 55.750 ;
        RECT 42.970 55.200 43.050 55.750 ;
        RECT 43.890 55.200 43.970 55.750 ;
        RECT 44.810 55.200 44.890 55.750 ;
        RECT 45.730 55.200 45.810 55.750 ;
        RECT 46.650 55.200 46.730 55.750 ;
        RECT 47.570 55.200 47.650 55.750 ;
        RECT 48.490 55.200 48.570 55.750 ;
        RECT 49.410 55.200 49.490 55.750 ;
        RECT 50.330 55.200 50.410 55.750 ;
        RECT 51.250 55.200 51.330 55.750 ;
        RECT 52.170 55.200 52.250 55.750 ;
        RECT 53.090 55.200 53.170 55.750 ;
        RECT 54.010 55.200 54.090 55.750 ;
        RECT 54.930 55.200 55.010 55.750 ;
        RECT 55.850 55.200 55.930 55.750 ;
        RECT 56.770 55.200 56.850 55.750 ;
        RECT 57.690 55.200 57.770 55.750 ;
        RECT 58.610 55.200 58.690 55.750 ;
        RECT 59.530 55.200 59.610 55.750 ;
        RECT 60.450 55.200 60.530 55.750 ;
        RECT 61.370 55.200 61.450 55.750 ;
        RECT 62.290 55.200 62.370 55.750 ;
        RECT 63.210 55.200 63.290 55.750 ;
        RECT 64.130 55.200 64.210 55.750 ;
        RECT 65.050 55.200 65.130 55.750 ;
        RECT 65.970 55.200 66.050 55.750 ;
        RECT 66.890 55.200 66.970 55.750 ;
        RECT 67.810 55.200 67.890 55.750 ;
        RECT 68.730 55.200 68.810 55.750 ;
        RECT 69.650 55.200 69.730 55.750 ;
        RECT 70.570 55.200 70.650 55.750 ;
        RECT 71.490 55.200 71.570 55.750 ;
        RECT 72.410 55.200 72.490 55.750 ;
        RECT 73.330 55.200 73.410 55.750 ;
        RECT 74.250 55.200 74.330 55.750 ;
        RECT 75.170 55.200 75.250 55.750 ;
        RECT 76.090 55.200 76.170 55.750 ;
        RECT 77.010 55.200 77.090 55.750 ;
        RECT 77.930 55.200 78.010 55.750 ;
        RECT 78.850 55.200 78.930 55.750 ;
        RECT 79.770 55.200 79.850 55.750 ;
        RECT 80.690 55.200 80.770 55.750 ;
        RECT 81.610 55.200 81.690 55.750 ;
        RECT 82.530 55.200 82.610 55.750 ;
        RECT 83.450 55.200 83.530 55.750 ;
        RECT 84.370 55.200 84.450 55.750 ;
        RECT 85.290 55.200 85.370 55.750 ;
        RECT 86.210 55.200 86.290 55.750 ;
        RECT 87.130 55.200 87.210 55.750 ;
        RECT 88.050 55.200 88.130 55.750 ;
        RECT 88.970 55.200 89.050 55.750 ;
        RECT 89.890 55.200 89.970 55.750 ;
        RECT 90.810 55.200 90.890 55.750 ;
        RECT 91.730 55.200 91.810 55.750 ;
        RECT 92.650 55.200 92.730 55.750 ;
        RECT 93.570 55.200 93.650 55.750 ;
        RECT 94.490 55.200 94.570 55.750 ;
        RECT 95.410 55.200 95.490 55.750 ;
        RECT 96.330 55.200 96.410 55.750 ;
        RECT 97.250 55.200 97.330 55.750 ;
        RECT 98.170 55.200 98.250 55.750 ;
        RECT 99.090 55.200 99.170 55.750 ;
        RECT 100.010 55.200 100.090 55.750 ;
        RECT 100.930 55.200 101.010 55.750 ;
        RECT 101.850 55.200 101.930 55.750 ;
        RECT 102.770 55.200 115.360 55.750 ;
        RECT 1.010 0.560 115.360 55.200 ;
        RECT 1.010 0.010 4.410 0.560 ;
        RECT 5.250 0.010 9.930 0.560 ;
        RECT 10.770 0.010 15.450 0.560 ;
        RECT 16.290 0.010 20.970 0.560 ;
        RECT 21.810 0.010 26.490 0.560 ;
        RECT 27.330 0.010 32.010 0.560 ;
        RECT 32.850 0.010 37.530 0.560 ;
        RECT 38.370 0.010 43.050 0.560 ;
        RECT 43.890 0.010 48.570 0.560 ;
        RECT 49.410 0.010 54.090 0.560 ;
        RECT 54.930 0.010 59.610 0.560 ;
        RECT 60.450 0.010 65.130 0.560 ;
        RECT 65.970 0.010 70.650 0.560 ;
        RECT 71.490 0.010 76.170 0.560 ;
        RECT 77.010 0.010 81.690 0.560 ;
        RECT 82.530 0.010 87.210 0.560 ;
        RECT 88.050 0.010 92.730 0.560 ;
        RECT 93.570 0.010 98.250 0.560 ;
        RECT 99.090 0.010 103.770 0.560 ;
        RECT 104.610 0.010 109.290 0.560 ;
        RECT 110.130 0.010 114.810 0.560 ;
      LAYER met3 ;
        RECT 0.600 48.640 119.460 48.785 ;
        RECT 1.000 5.615 119.060 48.640 ;
      LAYER met4 ;
        RECT 43.535 33.495 44.620 46.065 ;
        RECT 47.020 33.495 47.545 46.065 ;
  END
END S_term_OpenRAM
END LIBRARY

